VERSION 5.7 ;
BUSBITCHARS "[]" ;
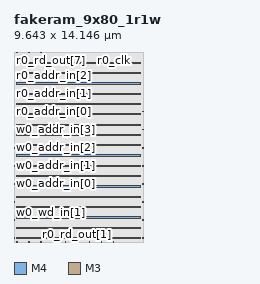
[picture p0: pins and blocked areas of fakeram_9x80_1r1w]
MACRO fakeram_9x80_1r1w
  FOREIGN fakeram_9x80_1r1w 0 0 ;
  SYMMETRY X Y R90 ;
  SIZE 9.643 BY 14.146 ;
  CLASS BLOCK ;
  PIN w0_wd_in[0]
    DIRECTION INPUT ;
    USE SIGNAL ;
    SHAPE ABUTMENT ;
    PORT
      LAYER M4 ;
      RECT 0.000 0.276 0.072 0.300 ;
    END
  END w0_wd_in[0]
  PIN w0_wd_in[1]
    DIRECTION INPUT ;
    USE SIGNAL ;
    SHAPE ABUTMENT ;
    PORT
      LAYER M4 ;
      RECT 0.000 1.620 0.072 1.644 ;
    END
  END w0_wd_in[1]
  PIN w0_wd_in[2]
    DIRECTION INPUT ;
    USE SIGNAL ;
    SHAPE ABUTMENT ;
    PORT
      LAYER M4 ;
      RECT 0.000 2.964 0.072 2.988 ;
    END
  END w0_wd_in[2]
  PIN w0_wd_in[3]
    DIRECTION INPUT ;
    USE SIGNAL ;
    SHAPE ABUTMENT ;
    PORT
      LAYER M4 ;
      RECT 9.571 0.276 9.643 0.300 ;
    END
  END w0_wd_in[3]
  PIN w0_wd_in[4]
    DIRECTION INPUT ;
    USE SIGNAL ;
    SHAPE ABUTMENT ;
    PORT
      LAYER M4 ;
      RECT 9.571 1.620 9.643 1.644 ;
    END
  END w0_wd_in[4]
  PIN w0_wd_in[5]
    DIRECTION OUTPUT ;
    USE SIGNAL ;
    SHAPE ABUTMENT ;
    PORT
      LAYER M3 ;
      RECT 0.207 0.000 0.225 0.054 ;
    END
  END w0_wd_in[5]
  PIN w0_wd_in[6]
    DIRECTION OUTPUT ;
    USE SIGNAL ;
    SHAPE ABUTMENT ;
    PORT
      LAYER M3 ;
      RECT 1.107 0.000 1.125 0.054 ;
    END
  END w0_wd_in[6]
  PIN w0_wd_in[7]
    DIRECTION OUTPUT ;
    USE SIGNAL ;
    SHAPE ABUTMENT ;
    PORT
      LAYER M3 ;
      RECT 2.007 0.000 2.025 0.054 ;
    END
  END w0_wd_in[7]
  PIN w0_wd_in[8]
    DIRECTION OUTPUT ;
    USE SIGNAL ;
    SHAPE ABUTMENT ;
    PORT
      LAYER M3 ;
      RECT 2.907 0.000 2.925 0.054 ;
    END
  END w0_wd_in[8]
  PIN r0_rd_out[0]
    DIRECTION OUTPUT ;
    USE SIGNAL ;
    SHAPE ABUTMENT ;
    PORT
      LAYER M3 ;
      RECT 3.807 0.000 3.825 0.054 ;
    END
  END r0_rd_out[0]
  PIN r0_rd_out[1]
    DIRECTION OUTPUT ;
    USE SIGNAL ;
    SHAPE ABUTMENT ;
    PORT
      LAYER M3 ;
      RECT 4.707 0.000 4.725 0.054 ;
    END
  END r0_rd_out[1]
  PIN r0_rd_out[2]
    DIRECTION OUTPUT ;
    USE SIGNAL ;
    SHAPE ABUTMENT ;
    PORT
      LAYER M3 ;
      RECT 5.607 0.000 5.625 0.054 ;
    END
  END r0_rd_out[2]
  PIN r0_rd_out[3]
    DIRECTION OUTPUT ;
    USE SIGNAL ;
    SHAPE ABUTMENT ;
    PORT
      LAYER M3 ;
      RECT 6.507 0.000 6.525 0.054 ;
    END
  END r0_rd_out[3]
  PIN r0_rd_out[4]
    DIRECTION OUTPUT ;
    USE SIGNAL ;
    SHAPE ABUTMENT ;
    PORT
      LAYER M3 ;
      RECT 7.407 0.000 7.425 0.054 ;
    END
  END r0_rd_out[4]
  PIN r0_rd_out[5]
    DIRECTION OUTPUT ;
    USE SIGNAL ;
    SHAPE ABUTMENT ;
    PORT
      LAYER M3 ;
      RECT 0.207 14.092 0.225 14.146 ;
    END
  END r0_rd_out[5]
  PIN r0_rd_out[6]
    DIRECTION OUTPUT ;
    USE SIGNAL ;
    SHAPE ABUTMENT ;
    PORT
      LAYER M3 ;
      RECT 1.107 14.092 1.125 14.146 ;
    END
  END r0_rd_out[6]
  PIN r0_rd_out[7]
    DIRECTION OUTPUT ;
    USE SIGNAL ;
    SHAPE ABUTMENT ;
    PORT
      LAYER M3 ;
      RECT 2.007 14.092 2.025 14.146 ;
    END
  END r0_rd_out[7]
  PIN r0_rd_out[8]
    DIRECTION OUTPUT ;
    USE SIGNAL ;
    SHAPE ABUTMENT ;
    PORT
      LAYER M3 ;
      RECT 2.907 14.092 2.925 14.146 ;
    END
  END r0_rd_out[8]
  PIN w0_addr_in[0]
    DIRECTION INPUT ;
    USE SIGNAL ;
    SHAPE ABUTMENT ;
    PORT
      LAYER M4 ;
      RECT 0.000 4.308 0.072 4.332 ;
    END
  END w0_addr_in[0]
  PIN w0_addr_in[1]
    DIRECTION INPUT ;
    USE SIGNAL ;
    SHAPE ABUTMENT ;
    PORT
      LAYER M4 ;
      RECT 0.000 5.652 0.072 5.676 ;
    END
  END w0_addr_in[1]
  PIN w0_addr_in[2]
    DIRECTION INPUT ;
    USE SIGNAL ;
    SHAPE ABUTMENT ;
    PORT
      LAYER M4 ;
      RECT 0.000 6.996 0.072 7.020 ;
    END
  END w0_addr_in[2]
  PIN w0_addr_in[3]
    DIRECTION INPUT ;
    USE SIGNAL ;
    SHAPE ABUTMENT ;
    PORT
      LAYER M4 ;
      RECT 0.000 8.340 0.072 8.364 ;
    END
  END w0_addr_in[3]
  PIN w0_addr_in[4]
    DIRECTION INPUT ;
    USE SIGNAL ;
    SHAPE ABUTMENT ;
    PORT
      LAYER M4 ;
      RECT 9.571 2.964 9.643 2.988 ;
    END
  END w0_addr_in[4]
  PIN w0_addr_in[5]
    DIRECTION INPUT ;
    USE SIGNAL ;
    SHAPE ABUTMENT ;
    PORT
      LAYER M4 ;
      RECT 9.571 4.308 9.643 4.332 ;
    END
  END w0_addr_in[5]
  PIN w0_addr_in[6]
    DIRECTION INPUT ;
    USE SIGNAL ;
    SHAPE ABUTMENT ;
    PORT
      LAYER M4 ;
      RECT 9.571 5.652 9.643 5.676 ;
    END
  END w0_addr_in[6]
  PIN r0_addr_in[0]
    DIRECTION INPUT ;
    USE SIGNAL ;
    SHAPE ABUTMENT ;
    PORT
      LAYER M4 ;
      RECT 0.000 9.684 0.072 9.708 ;
    END
  END r0_addr_in[0]
  PIN r0_addr_in[1]
    DIRECTION INPUT ;
    USE SIGNAL ;
    SHAPE ABUTMENT ;
    PORT
      LAYER M4 ;
      RECT 0.000 11.028 0.072 11.052 ;
    END
  END r0_addr_in[1]
  PIN r0_addr_in[2]
    DIRECTION INPUT ;
    USE SIGNAL ;
    SHAPE ABUTMENT ;
    PORT
      LAYER M4 ;
      RECT 0.000 12.372 0.072 12.396 ;
    END
  END r0_addr_in[2]
  PIN r0_addr_in[3]
    DIRECTION INPUT ;
    USE SIGNAL ;
    SHAPE ABUTMENT ;
    PORT
      LAYER M4 ;
      RECT 0.000 13.716 0.072 13.740 ;
    END
  END r0_addr_in[3]
  PIN r0_addr_in[4]
    DIRECTION INPUT ;
    USE SIGNAL ;
    SHAPE ABUTMENT ;
    PORT
      LAYER M4 ;
      RECT 9.571 6.996 9.643 7.020 ;
    END
  END r0_addr_in[4]
  PIN r0_addr_in[5]
    DIRECTION INPUT ;
    USE SIGNAL ;
    SHAPE ABUTMENT ;
    PORT
      LAYER M4 ;
      RECT 9.571 8.340 9.643 8.364 ;
    END
  END r0_addr_in[5]
  PIN r0_addr_in[6]
    DIRECTION INPUT ;
    USE SIGNAL ;
    SHAPE ABUTMENT ;
    PORT
      LAYER M4 ;
      RECT 9.571 9.684 9.643 9.708 ;
    END
  END r0_addr_in[6]
  PIN w0_we_in
    DIRECTION INPUT ;
    USE SIGNAL ;
    SHAPE ABUTMENT ;
    PORT
      LAYER M3 ;
      RECT 3.807 14.092 3.825 14.146 ;
    END
  END w0_we_in
  PIN w0_ce_in
    DIRECTION INPUT ;
    USE SIGNAL ;
    SHAPE ABUTMENT ;
    PORT
      LAYER M3 ;
      RECT 4.707 14.092 4.725 14.146 ;
    END
  END w0_ce_in
  PIN w0_clk
    DIRECTION INPUT ;
    USE SIGNAL ;
    SHAPE ABUTMENT ;
    PORT
      LAYER M3 ;
      RECT 5.607 14.092 5.625 14.146 ;
    END
  END w0_clk
  PIN r0_ce_in
    DIRECTION INPUT ;
    USE SIGNAL ;
    SHAPE ABUTMENT ;
    PORT
      LAYER M3 ;
      RECT 6.507 14.092 6.525 14.146 ;
    END
  END r0_ce_in
  PIN r0_clk
    DIRECTION INPUT ;
    USE SIGNAL ;
    SHAPE ABUTMENT ;
    PORT
      LAYER M3 ;
      RECT 7.407 14.092 7.425 14.146 ;
    END
  END r0_clk
  PIN VSS
    DIRECTION INOUT ;
    USE GROUND ;
    PORT
      LAYER M4 ;
      RECT 0.216 0.240 9.427 0.336 ;
      RECT 0.216 1.008 9.427 1.104 ;
      RECT 0.216 1.776 9.427 1.872 ;
      RECT 0.216 2.544 9.427 2.640 ;
      RECT 0.216 3.312 9.427 3.408 ;
      RECT 0.216 4.080 9.427 4.176 ;
      RECT 0.216 4.848 9.427 4.944 ;
      RECT 0.216 5.616 9.427 5.712 ;
      RECT 0.216 6.384 9.427 6.480 ;
      RECT 0.216 7.152 9.427 7.248 ;
      RECT 0.216 7.920 9.427 8.016 ;
      RECT 0.216 8.688 9.427 8.784 ;
      RECT 0.216 9.456 9.427 9.552 ;
      RECT 0.216 10.224 9.427 10.320 ;
      RECT 0.216 10.992 9.427 11.088 ;
      RECT 0.216 11.760 9.427 11.856 ;
      RECT 0.216 12.528 9.427 12.624 ;
      RECT 0.216 13.296 9.427 13.392 ;
    END
  END VSS
  PIN VDD
    DIRECTION INOUT ;
    USE POWER ;
    PORT
      LAYER M4 ;
      RECT 0.216 0.240 9.427 0.336 ;
      RECT 0.216 1.008 9.427 1.104 ;
      RECT 0.216 1.776 9.427 1.872 ;
      RECT 0.216 2.544 9.427 2.640 ;
      RECT 0.216 3.312 9.427 3.408 ;
      RECT 0.216 4.080 9.427 4.176 ;
      RECT 0.216 4.848 9.427 4.944 ;
      RECT 0.216 5.616 9.427 5.712 ;
      RECT 0.216 6.384 9.427 6.480 ;
      RECT 0.216 7.152 9.427 7.248 ;
      RECT 0.216 7.920 9.427 8.016 ;
      RECT 0.216 8.688 9.427 8.784 ;
      RECT 0.216 9.456 9.427 9.552 ;
      RECT 0.216 10.224 9.427 10.320 ;
      RECT 0.216 10.992 9.427 11.088 ;
      RECT 0.216 11.760 9.427 11.856 ;
      RECT 0.216 12.528 9.427 12.624 ;
      RECT 0.216 13.296 9.427 13.392 ;
    END
  END VDD
  OBS
    LAYER M1 ;
    RECT 0 0 9.643 14.146 ;
    LAYER M2 ;
    RECT 0 0 9.643 14.146 ;
    LAYER M3 ;
    RECT 0 0 9.643 14.146 ;
    LAYER M4 ;
    RECT 0 0 9.643 14.146 ;
  END
END fakeram_9x80_1r1w

END LIBRARY
